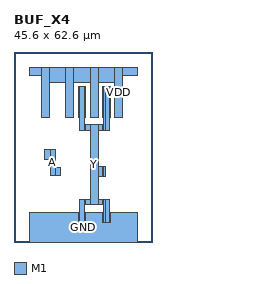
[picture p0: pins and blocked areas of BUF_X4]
MACRO BUF_X4
  CLASS CORE ;
  ORIGIN 0 0 ;
  SIZE 45.600 BY 62.600 ;
  SYMMETRY X Y ;
  SITE TR1um_site ;
  PIN Y
    DIRECTION OUTPUT ;
    USE SIGNAL ;
    PORT
      LAYER M1 ;
        RECT 21.100 6.400 21.500 9.800 ;
      LAYER M1 ;
        RECT 21.100 41.000 21.500 51.200 ;
      LAYER M1 ;
        RECT 21.500 6.400 23.300 14.000 ;
      LAYER M1 ;
        RECT 21.500 36.800 23.300 51.200 ;
      LAYER M1 ;
        RECT 23.300 6.400 23.700 9.800 ;
      LAYER M1 ;
        RECT 23.300 12.200 23.700 14.000 ;
      LAYER M1 ;
        RECT 23.300 36.800 23.700 38.600 ;
      LAYER M1 ;
        RECT 23.300 41.000 23.700 51.200 ;
      LAYER M1 ;
        RECT 23.700 12.200 25.100 14.000 ;
      LAYER M1 ;
        RECT 23.700 36.800 25.100 38.600 ;
      LAYER M1 ;
        RECT 25.100 12.200 27.700 38.600 ;
      LAYER M1 ;
        RECT 27.700 12.200 29.100 14.000 ;
      LAYER M1 ;
        RECT 27.700 21.600 29.100 25.000 ;
      LAYER M1 ;
        RECT 27.700 36.800 29.100 38.600 ;
      LAYER M1 ;
        RECT 29.100 6.400 29.500 9.800 ;
      LAYER M1 ;
        RECT 29.100 12.200 29.500 14.000 ;
      LAYER M1 ;
        RECT 29.100 21.600 29.500 25.000 ;
      LAYER M1 ;
        RECT 29.100 36.800 29.500 38.600 ;
      LAYER M1 ;
        RECT 29.100 41.000 29.500 51.200 ;
      LAYER M1 ;
        RECT 29.500 6.400 30.000 14.000 ;
      LAYER M1 ;
        RECT 29.500 21.600 30.000 25.000 ;
      LAYER M1 ;
        RECT 29.500 36.800 30.000 51.200 ;
      LAYER M1 ;
        RECT 30.000 6.400 31.300 14.000 ;
      LAYER M1 ;
        RECT 30.000 36.800 31.300 51.200 ;
      LAYER M1 ;
        RECT 31.300 6.400 31.700 9.800 ;
      LAYER M1 ;
        RECT 31.300 41.000 31.700 51.200 ;
    END
  END Y
  PIN A
    DIRECTION INPUT ;
    USE SIGNAL ;
    PORT
      LAYER M1 ;
        RECT 10.100 27.100 11.900 30.500 ;
      LAYER M1 ;
        RECT 11.900 22.000 13.700 30.500 ;
      LAYER M1 ;
        RECT 13.700 22.000 15.400 24.600 ;
    END
  END A
  PIN VDD
    DIRECTION INOUT ;
    USE POWER ;
    PORT
      LAYER M1 ;
        RECT 5.000 55.000 9.100 57.600 ;
      LAYER M1 ;
        RECT 9.100 41.000 11.700 57.600 ;
      LAYER M1 ;
        RECT 11.700 52.600 17.100 57.600 ;
      LAYER M1 ;
        RECT 17.100 41.000 19.700 57.600 ;
      LAYER M1 ;
        RECT 19.700 52.600 25.100 57.600 ;
      LAYER M1 ;
        RECT 25.100 41.000 27.700 57.600 ;
      LAYER M1 ;
        RECT 27.700 52.600 33.100 57.600 ;
      LAYER M1 ;
        RECT 33.100 41.000 35.700 57.600 ;
      LAYER M1 ;
        RECT 35.700 55.000 40.600 57.600 ;
    END
  END VDD
  PIN GND
    DIRECTION INOUT ;
    USE GROUND ;
    PORT
      LAYER M1 ;
        RECT 5.000 0.000 40.600 9.800 ;
    END
  END GND
END BUF_X4
